VERSION 5.7 ;
  NOWIREEXTENSIONATPIN ON ;
  DIVIDERCHAR "/" ;
  BUSBITCHARS "[]" ;
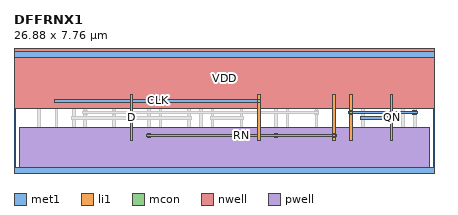
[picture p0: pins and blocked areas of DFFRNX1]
MACRO DFFRNX1
  CLASS CORE ;
  FOREIGN DFFRNX1 ;
  ORIGIN 0.000 0.000 ;
  SIZE 26.880 BY 7.760 ;
  SYMMETRY X Y ;
  SITE unitrh ;
  PIN Q
    DIRECTION OUTPUT ;
    USE SIGNAL ;
    ANTENNAGATEAREA 1.027250 ;
    ANTENNADIFFAREA 1.351900 ;
    PORT
      LAYER met1 ;
        RECT 21.465 3.965 21.695 3.995 ;
        RECT 25.535 3.965 25.765 3.995 ;
        RECT 21.435 3.795 25.795 3.965 ;
        RECT 21.465 3.765 21.695 3.795 ;
        RECT 25.535 3.765 25.765 3.795 ;
    END
    PORT
      LAYER li1 ;
        RECT 21.495 2.095 21.665 5.045 ;
      LAYER mcon ;
        RECT 21.495 3.795 21.665 3.965 ;
    END
  END Q
  PIN QN
    DIRECTION OUTPUT ;
    USE SIGNAL ;
    ANTENNAGATEAREA 1.033250 ;
    ANTENNADIFFAREA 1.931900 ;
    PORT
      LAYER met1 ;
        RECT 22.205 3.595 22.435 3.625 ;
        RECT 24.055 3.595 24.285 3.625 ;
        RECT 22.175 3.425 24.315 3.595 ;
        RECT 22.205 3.395 22.435 3.425 ;
        RECT 24.055 3.395 24.285 3.425 ;
    END
    PORT
      LAYER li1 ;
        RECT 24.085 2.095 24.255 5.045 ;
      LAYER mcon ;
        RECT 24.085 3.425 24.255 3.595 ;
    END
  END QN
  PIN D
    DIRECTION INPUT ;
    USE SIGNAL ;
    ANTENNAGATEAREA 1.014850 ;
    PORT
      LAYER li1 ;
        RECT 7.435 2.095 7.605 5.045 ;
    END
  END D
  PIN CLK
    DIRECTION INPUT ;
    USE SIGNAL ;
    ANTENNAGATEAREA 2.029700 ;
    PORT
      LAYER met1 ;
        RECT 2.595 4.705 2.825 4.735 ;
        RECT 15.545 4.705 15.775 4.735 ;
        RECT 2.565 4.535 15.805 4.705 ;
        RECT 2.595 4.505 2.825 4.535 ;
        RECT 15.545 4.505 15.775 4.535 ;
    END
    PORT
      LAYER li1 ;
        RECT 15.575 2.095 15.745 5.045 ;
      LAYER mcon ;
        RECT 15.575 4.535 15.745 4.705 ;
    END
  END CLK
  PIN RN
    DIRECTION INPUT ;
    USE SIGNAL ;
    ANTENNAGATEAREA 3.069350 ;
    PORT
      LAYER met1 ;
        RECT 8.515 2.485 8.745 2.515 ;
        RECT 16.655 2.485 16.885 2.515 ;
        RECT 20.355 2.485 20.585 2.515 ;
        RECT 8.485 2.315 20.615 2.485 ;
        RECT 8.515 2.285 8.745 2.315 ;
        RECT 16.655 2.285 16.885 2.315 ;
        RECT 20.355 2.285 20.585 2.315 ;
    END
    PORT
      LAYER li1 ;
        RECT 20.385 2.095 20.555 5.045 ;
      LAYER mcon ;
        RECT 20.385 2.315 20.555 2.485 ;
    END
  END RN
  PIN VDD
    DIRECTION INOUT ;
    USE POWER ;
    SHAPE ABUTMENT ;
    PORT
      LAYER nwell ;
        RECT 0.000 4.110 26.880 7.940 ;
      LAYER met1 ;
        RECT 0.000 7.410 26.880 7.760 ;
    END
    PORT
      LAYER pwell ;
        RECT 0.320 0.000 26.560 2.900 ;
      LAYER met1 ;
        RECT 0.000 0.000 26.880 0.350 ;
    END
  END VDD
  OBS
      LAYER li1 ;
        RECT 0.000 7.410 26.880 7.760 ;
        RECT 0.320 4.290 0.660 7.410 ;
        RECT 1.495 5.395 1.665 7.410 ;
        RECT 1.935 5.420 2.105 7.200 ;
        RECT 2.375 5.735 2.545 7.410 ;
        RECT 2.815 5.420 2.985 7.200 ;
        RECT 3.255 5.735 3.425 7.410 ;
        RECT 3.695 5.420 3.865 7.200 ;
        RECT 4.135 5.735 4.305 7.410 ;
        RECT 1.935 5.250 4.645 5.420 ;
        RECT 0.320 0.350 0.660 2.900 ;
        RECT 1.515 2.095 1.685 5.045 ;
        RECT 2.625 2.095 2.795 5.045 ;
        RECT 3.735 2.095 3.905 5.045 ;
        RECT 0.995 1.855 1.165 1.935 ;
        RECT 1.965 1.855 2.135 1.935 ;
        RECT 2.935 1.855 3.105 1.935 ;
        RECT 0.995 1.685 3.105 1.855 ;
        RECT 0.995 0.555 1.165 1.685 ;
        RECT 1.480 0.350 1.650 1.310 ;
        RECT 1.965 0.805 2.135 1.685 ;
        RECT 2.935 1.605 3.105 1.685 ;
        RECT 2.455 1.260 2.625 1.340 ;
        RECT 3.505 1.260 3.675 1.935 ;
        RECT 4.475 1.930 4.645 5.250 ;
        RECT 5.130 4.290 5.470 7.410 ;
        RECT 6.305 5.395 6.475 7.410 ;
        RECT 6.745 5.420 6.915 7.200 ;
        RECT 7.185 5.735 7.355 7.410 ;
        RECT 7.625 5.420 7.795 7.200 ;
        RECT 8.065 5.735 8.235 7.410 ;
        RECT 8.505 5.420 8.675 7.200 ;
        RECT 8.945 5.735 9.115 7.410 ;
        RECT 6.745 5.250 9.455 5.420 ;
        RECT 2.455 1.090 3.675 1.260 ;
        RECT 2.455 1.010 2.625 1.090 ;
        RECT 2.935 0.805 3.105 0.885 ;
        RECT 1.965 0.635 3.105 0.805 ;
        RECT 1.965 0.555 2.135 0.635 ;
        RECT 2.935 0.555 3.105 0.635 ;
        RECT 3.505 0.805 3.675 1.090 ;
        RECT 3.990 1.760 4.645 1.930 ;
        RECT 3.990 1.025 4.160 1.760 ;
        RECT 4.475 0.805 4.645 1.575 ;
        RECT 3.505 0.635 4.645 0.805 ;
        RECT 3.505 0.555 3.675 0.635 ;
        RECT 4.475 0.555 4.645 0.635 ;
        RECT 5.130 0.350 5.470 2.900 ;
        RECT 6.325 2.095 6.495 5.045 ;
        RECT 8.545 2.095 8.715 5.045 ;
        RECT 5.805 1.855 5.975 1.935 ;
        RECT 6.775 1.855 6.945 1.935 ;
        RECT 7.745 1.855 7.915 1.935 ;
        RECT 5.805 1.685 7.915 1.855 ;
        RECT 5.805 0.555 5.975 1.685 ;
        RECT 6.290 0.350 6.460 1.310 ;
        RECT 6.775 0.805 6.945 1.685 ;
        RECT 7.745 1.605 7.915 1.685 ;
        RECT 7.265 1.260 7.435 1.340 ;
        RECT 8.315 1.260 8.485 1.935 ;
        RECT 9.285 1.930 9.455 5.250 ;
        RECT 9.940 4.290 10.280 7.410 ;
        RECT 10.815 5.315 10.985 7.410 ;
        RECT 11.255 5.465 11.425 7.200 ;
        RECT 11.695 5.735 11.865 7.410 ;
        RECT 12.135 5.465 12.305 7.200 ;
        RECT 12.575 5.735 12.745 7.410 ;
        RECT 11.255 5.295 12.785 5.465 ;
        RECT 7.265 1.090 8.485 1.260 ;
        RECT 7.265 1.010 7.435 1.090 ;
        RECT 7.745 0.805 7.915 0.885 ;
        RECT 6.775 0.635 7.915 0.805 ;
        RECT 6.775 0.555 6.945 0.635 ;
        RECT 7.745 0.555 7.915 0.635 ;
        RECT 8.315 0.805 8.485 1.090 ;
        RECT 8.800 1.760 9.455 1.930 ;
        RECT 8.800 1.025 8.970 1.760 ;
        RECT 9.285 0.805 9.455 1.575 ;
        RECT 8.315 0.635 9.455 0.805 ;
        RECT 8.315 0.555 8.485 0.635 ;
        RECT 9.285 0.555 9.455 0.635 ;
        RECT 9.940 0.350 10.280 2.900 ;
        RECT 11.135 2.095 11.305 5.045 ;
        RECT 11.905 4.890 12.075 5.045 ;
        RECT 11.875 4.715 12.075 4.890 ;
        RECT 11.875 2.095 12.045 4.715 ;
        RECT 10.720 1.845 10.890 1.925 ;
        RECT 11.690 1.845 11.860 1.925 ;
        RECT 12.615 1.920 12.785 5.295 ;
        RECT 13.270 4.290 13.610 7.410 ;
        RECT 14.445 5.395 14.615 7.410 ;
        RECT 14.885 5.420 15.055 7.200 ;
        RECT 15.325 5.735 15.495 7.410 ;
        RECT 15.765 5.420 15.935 7.200 ;
        RECT 16.205 5.735 16.375 7.410 ;
        RECT 16.645 5.420 16.815 7.200 ;
        RECT 17.085 5.735 17.255 7.410 ;
        RECT 14.885 5.250 17.595 5.420 ;
        RECT 10.720 1.675 11.860 1.845 ;
        RECT 10.720 0.545 10.890 1.675 ;
        RECT 11.205 0.350 11.375 1.300 ;
        RECT 11.690 0.795 11.860 1.675 ;
        RECT 12.175 1.750 12.785 1.920 ;
        RECT 12.175 1.015 12.345 1.750 ;
        RECT 12.660 0.795 12.830 1.565 ;
        RECT 11.690 0.625 12.830 0.795 ;
        RECT 11.690 0.545 11.860 0.625 ;
        RECT 12.660 0.545 12.830 0.625 ;
        RECT 13.270 0.350 13.610 2.900 ;
        RECT 14.465 2.095 14.635 5.045 ;
        RECT 16.685 2.095 16.855 5.045 ;
        RECT 13.945 1.855 14.115 1.935 ;
        RECT 14.915 1.855 15.085 1.935 ;
        RECT 15.885 1.855 16.055 1.935 ;
        RECT 13.945 1.685 16.055 1.855 ;
        RECT 13.945 0.555 14.115 1.685 ;
        RECT 14.430 0.350 14.600 1.310 ;
        RECT 14.915 0.805 15.085 1.685 ;
        RECT 15.885 1.605 16.055 1.685 ;
        RECT 15.405 1.260 15.575 1.340 ;
        RECT 16.455 1.260 16.625 1.935 ;
        RECT 17.425 1.930 17.595 5.250 ;
        RECT 18.080 4.290 18.420 7.410 ;
        RECT 19.255 5.395 19.425 7.410 ;
        RECT 19.695 5.420 19.865 7.200 ;
        RECT 20.135 5.735 20.305 7.410 ;
        RECT 20.575 5.420 20.745 7.200 ;
        RECT 21.015 5.735 21.185 7.410 ;
        RECT 21.455 5.420 21.625 7.200 ;
        RECT 21.895 5.735 22.065 7.410 ;
        RECT 19.695 5.250 22.405 5.420 ;
        RECT 15.405 1.090 16.625 1.260 ;
        RECT 15.405 1.010 15.575 1.090 ;
        RECT 15.885 0.805 16.055 0.885 ;
        RECT 14.915 0.635 16.055 0.805 ;
        RECT 14.915 0.555 15.085 0.635 ;
        RECT 15.885 0.555 16.055 0.635 ;
        RECT 16.455 0.805 16.625 1.090 ;
        RECT 16.940 1.760 17.595 1.930 ;
        RECT 16.940 1.025 17.110 1.760 ;
        RECT 17.425 0.805 17.595 1.575 ;
        RECT 16.455 0.635 17.595 0.805 ;
        RECT 16.455 0.555 16.625 0.635 ;
        RECT 17.425 0.555 17.595 0.635 ;
        RECT 18.080 0.350 18.420 2.900 ;
        RECT 19.275 2.095 19.445 5.045 ;
        RECT 18.755 1.855 18.925 1.935 ;
        RECT 19.725 1.855 19.895 1.935 ;
        RECT 20.695 1.855 20.865 1.935 ;
        RECT 18.755 1.685 20.865 1.855 ;
        RECT 18.755 0.555 18.925 1.685 ;
        RECT 19.240 0.350 19.410 1.310 ;
        RECT 19.725 0.805 19.895 1.685 ;
        RECT 20.695 1.605 20.865 1.685 ;
        RECT 20.215 1.260 20.385 1.340 ;
        RECT 21.265 1.260 21.435 1.935 ;
        RECT 22.235 1.930 22.405 5.250 ;
        RECT 22.890 4.290 23.230 7.410 ;
        RECT 23.765 5.315 23.935 7.410 ;
        RECT 24.205 5.465 24.375 7.200 ;
        RECT 24.645 5.735 24.815 7.410 ;
        RECT 25.085 5.465 25.255 7.200 ;
        RECT 25.525 5.735 25.695 7.410 ;
        RECT 24.205 5.295 25.735 5.465 ;
        RECT 24.855 4.890 25.025 5.045 ;
        RECT 24.825 4.715 25.025 4.890 ;
        RECT 20.215 1.090 21.435 1.260 ;
        RECT 20.215 1.010 20.385 1.090 ;
        RECT 20.695 0.805 20.865 0.885 ;
        RECT 19.725 0.635 20.865 0.805 ;
        RECT 19.725 0.555 19.895 0.635 ;
        RECT 20.695 0.555 20.865 0.635 ;
        RECT 21.265 0.805 21.435 1.090 ;
        RECT 21.750 1.760 22.405 1.930 ;
        RECT 21.750 1.025 21.920 1.760 ;
        RECT 22.235 0.805 22.405 1.575 ;
        RECT 21.265 0.635 22.405 0.805 ;
        RECT 21.265 0.555 21.435 0.635 ;
        RECT 22.235 0.555 22.405 0.635 ;
        RECT 22.890 0.350 23.230 2.900 ;
        RECT 24.825 2.095 24.995 4.715 ;
        RECT 23.670 1.845 23.840 1.925 ;
        RECT 24.640 1.845 24.810 1.925 ;
        RECT 25.565 1.920 25.735 5.295 ;
        RECT 26.220 4.290 26.560 7.410 ;
        RECT 23.670 1.675 24.810 1.845 ;
        RECT 23.670 0.545 23.840 1.675 ;
        RECT 24.155 0.350 24.325 1.300 ;
        RECT 24.640 0.795 24.810 1.675 ;
        RECT 25.125 1.750 25.735 1.920 ;
        RECT 25.125 1.015 25.295 1.750 ;
        RECT 25.610 0.795 25.780 1.565 ;
        RECT 24.640 0.625 25.780 0.795 ;
        RECT 24.640 0.545 24.810 0.625 ;
        RECT 25.610 0.545 25.780 0.625 ;
        RECT 26.220 0.350 26.560 2.900 ;
        RECT 0.000 0.000 26.880 0.350 ;
      LAYER mcon ;
        RECT 0.775 7.495 0.945 7.665 ;
        RECT 1.145 7.495 1.315 7.665 ;
        RECT 1.515 7.495 1.685 7.665 ;
        RECT 1.885 7.495 2.055 7.665 ;
        RECT 2.255 7.495 2.425 7.665 ;
        RECT 2.625 7.495 2.795 7.665 ;
        RECT 2.995 7.495 3.165 7.665 ;
        RECT 3.365 7.495 3.535 7.665 ;
        RECT 3.735 7.495 3.905 7.665 ;
        RECT 4.105 7.495 4.275 7.665 ;
        RECT 4.475 7.495 4.645 7.665 ;
        RECT 4.845 7.495 5.015 7.665 ;
        RECT 5.585 7.495 5.755 7.665 ;
        RECT 5.955 7.495 6.125 7.665 ;
        RECT 6.325 7.495 6.495 7.665 ;
        RECT 6.695 7.495 6.865 7.665 ;
        RECT 7.065 7.495 7.235 7.665 ;
        RECT 7.435 7.495 7.605 7.665 ;
        RECT 7.805 7.495 7.975 7.665 ;
        RECT 8.175 7.495 8.345 7.665 ;
        RECT 8.545 7.495 8.715 7.665 ;
        RECT 8.915 7.495 9.085 7.665 ;
        RECT 9.285 7.495 9.455 7.665 ;
        RECT 9.655 7.495 9.825 7.665 ;
        RECT 10.395 7.495 10.565 7.665 ;
        RECT 10.765 7.495 10.935 7.665 ;
        RECT 11.135 7.495 11.305 7.665 ;
        RECT 11.505 7.495 11.675 7.665 ;
        RECT 11.875 7.495 12.045 7.665 ;
        RECT 12.245 7.495 12.415 7.665 ;
        RECT 12.615 7.495 12.785 7.665 ;
        RECT 12.985 7.495 13.155 7.665 ;
        RECT 13.725 7.495 13.895 7.665 ;
        RECT 14.095 7.495 14.265 7.665 ;
        RECT 14.465 7.495 14.635 7.665 ;
        RECT 14.835 7.495 15.005 7.665 ;
        RECT 15.205 7.495 15.375 7.665 ;
        RECT 15.575 7.495 15.745 7.665 ;
        RECT 15.945 7.495 16.115 7.665 ;
        RECT 16.315 7.495 16.485 7.665 ;
        RECT 16.685 7.495 16.855 7.665 ;
        RECT 17.055 7.495 17.225 7.665 ;
        RECT 17.425 7.495 17.595 7.665 ;
        RECT 17.795 7.495 17.965 7.665 ;
        RECT 18.535 7.495 18.705 7.665 ;
        RECT 18.905 7.495 19.075 7.665 ;
        RECT 19.275 7.495 19.445 7.665 ;
        RECT 19.645 7.495 19.815 7.665 ;
        RECT 20.015 7.495 20.185 7.665 ;
        RECT 20.385 7.495 20.555 7.665 ;
        RECT 20.755 7.495 20.925 7.665 ;
        RECT 21.125 7.495 21.295 7.665 ;
        RECT 21.495 7.495 21.665 7.665 ;
        RECT 21.865 7.495 22.035 7.665 ;
        RECT 22.235 7.495 22.405 7.665 ;
        RECT 22.605 7.495 22.775 7.665 ;
        RECT 23.345 7.495 23.515 7.665 ;
        RECT 23.715 7.495 23.885 7.665 ;
        RECT 24.085 7.495 24.255 7.665 ;
        RECT 24.455 7.495 24.625 7.665 ;
        RECT 24.825 7.495 24.995 7.665 ;
        RECT 25.195 7.495 25.365 7.665 ;
        RECT 25.565 7.495 25.735 7.665 ;
        RECT 25.935 7.495 26.105 7.665 ;
        RECT 1.515 4.165 1.685 4.335 ;
        RECT 2.625 4.535 2.795 4.705 ;
        RECT 3.735 3.425 3.905 3.595 ;
        RECT 4.475 3.795 4.645 3.965 ;
        RECT 6.325 3.795 6.495 3.965 ;
        RECT 8.545 2.315 8.715 2.485 ;
        RECT 9.285 3.425 9.455 3.595 ;
        RECT 11.135 3.425 11.305 3.595 ;
        RECT 11.875 4.165 12.045 4.335 ;
        RECT 12.615 3.425 12.785 3.595 ;
        RECT 14.465 3.425 14.635 3.595 ;
        RECT 16.685 2.315 16.855 2.485 ;
        RECT 17.425 4.165 17.595 4.335 ;
        RECT 19.275 3.795 19.445 3.965 ;
        RECT 22.235 3.425 22.405 3.595 ;
        RECT 24.825 4.165 24.995 4.335 ;
        RECT 25.565 3.795 25.735 3.965 ;
        RECT 0.775 0.095 0.945 0.265 ;
        RECT 1.145 0.095 1.315 0.265 ;
        RECT 1.515 0.095 1.685 0.265 ;
        RECT 1.885 0.095 2.055 0.265 ;
        RECT 2.255 0.095 2.425 0.265 ;
        RECT 2.625 0.095 2.795 0.265 ;
        RECT 2.995 0.095 3.165 0.265 ;
        RECT 3.365 0.095 3.535 0.265 ;
        RECT 3.735 0.095 3.905 0.265 ;
        RECT 4.105 0.095 4.275 0.265 ;
        RECT 4.475 0.095 4.645 0.265 ;
        RECT 4.845 0.095 5.015 0.265 ;
        RECT 5.585 0.095 5.755 0.265 ;
        RECT 5.955 0.095 6.125 0.265 ;
        RECT 6.325 0.095 6.495 0.265 ;
        RECT 6.695 0.095 6.865 0.265 ;
        RECT 7.065 0.095 7.235 0.265 ;
        RECT 7.435 0.095 7.605 0.265 ;
        RECT 7.805 0.095 7.975 0.265 ;
        RECT 8.175 0.095 8.345 0.265 ;
        RECT 8.545 0.095 8.715 0.265 ;
        RECT 8.915 0.095 9.085 0.265 ;
        RECT 9.285 0.095 9.455 0.265 ;
        RECT 9.655 0.095 9.825 0.265 ;
        RECT 10.395 0.095 10.565 0.265 ;
        RECT 10.765 0.095 10.935 0.265 ;
        RECT 11.135 0.095 11.305 0.265 ;
        RECT 11.505 0.095 11.675 0.265 ;
        RECT 11.875 0.095 12.045 0.265 ;
        RECT 12.245 0.095 12.415 0.265 ;
        RECT 12.615 0.095 12.785 0.265 ;
        RECT 12.985 0.095 13.155 0.265 ;
        RECT 13.725 0.095 13.895 0.265 ;
        RECT 14.095 0.095 14.265 0.265 ;
        RECT 14.465 0.095 14.635 0.265 ;
        RECT 14.835 0.095 15.005 0.265 ;
        RECT 15.205 0.095 15.375 0.265 ;
        RECT 15.575 0.095 15.745 0.265 ;
        RECT 15.945 0.095 16.115 0.265 ;
        RECT 16.315 0.095 16.485 0.265 ;
        RECT 16.685 0.095 16.855 0.265 ;
        RECT 17.055 0.095 17.225 0.265 ;
        RECT 17.425 0.095 17.595 0.265 ;
        RECT 17.795 0.095 17.965 0.265 ;
        RECT 18.535 0.095 18.705 0.265 ;
        RECT 18.905 0.095 19.075 0.265 ;
        RECT 19.275 0.095 19.445 0.265 ;
        RECT 19.645 0.095 19.815 0.265 ;
        RECT 20.015 0.095 20.185 0.265 ;
        RECT 20.385 0.095 20.555 0.265 ;
        RECT 20.755 0.095 20.925 0.265 ;
        RECT 21.125 0.095 21.295 0.265 ;
        RECT 21.495 0.095 21.665 0.265 ;
        RECT 21.865 0.095 22.035 0.265 ;
        RECT 22.235 0.095 22.405 0.265 ;
        RECT 22.605 0.095 22.775 0.265 ;
        RECT 23.345 0.095 23.515 0.265 ;
        RECT 23.715 0.095 23.885 0.265 ;
        RECT 24.085 0.095 24.255 0.265 ;
        RECT 24.455 0.095 24.625 0.265 ;
        RECT 24.825 0.095 24.995 0.265 ;
        RECT 25.195 0.095 25.365 0.265 ;
        RECT 25.565 0.095 25.735 0.265 ;
        RECT 25.935 0.095 26.105 0.265 ;
      LAYER met1 ;
        RECT 1.485 4.335 1.715 4.365 ;
        RECT 11.845 4.335 12.075 4.365 ;
        RECT 17.395 4.335 17.625 4.365 ;
        RECT 24.795 4.335 25.025 4.365 ;
        RECT 1.455 4.165 25.055 4.335 ;
        RECT 1.485 4.135 1.715 4.165 ;
        RECT 11.845 4.135 12.075 4.165 ;
        RECT 17.395 4.135 17.625 4.165 ;
        RECT 24.795 4.135 25.025 4.165 ;
        RECT 4.445 3.965 4.675 3.995 ;
        RECT 6.295 3.965 6.525 3.995 ;
        RECT 19.245 3.965 19.475 3.995 ;
        RECT 4.415 3.795 19.505 3.965 ;
        RECT 4.445 3.765 4.675 3.795 ;
        RECT 6.295 3.765 6.525 3.795 ;
        RECT 19.245 3.765 19.475 3.795 ;
        RECT 3.705 3.595 3.935 3.625 ;
        RECT 9.255 3.595 9.485 3.625 ;
        RECT 11.105 3.595 11.335 3.625 ;
        RECT 12.585 3.595 12.815 3.625 ;
        RECT 14.435 3.595 14.665 3.625 ;
        RECT 3.675 3.425 11.365 3.595 ;
        RECT 12.555 3.425 14.695 3.595 ;
        RECT 3.705 3.395 3.935 3.425 ;
        RECT 9.255 3.395 9.485 3.425 ;
        RECT 11.105 3.395 11.335 3.425 ;
        RECT 12.585 3.395 12.815 3.425 ;
        RECT 14.435 3.395 14.665 3.425 ;
  END
END DFFRNX1
END LIBRARY

